###############################################################
#  Generated by:      Cadence Innovus 21.37-s075_1
#  OS:                Linux x86_64(Host ID caen-vnc-mi04.engin.umich.edu)
#  Generated on:      Fri Feb 14 15:29:48 2025
#  Design:            xor_sbox
###############################################################

VERSION 5.8 ;

BUSBITCHARS "[]" ;
DIVIDERCHAR "/" ;

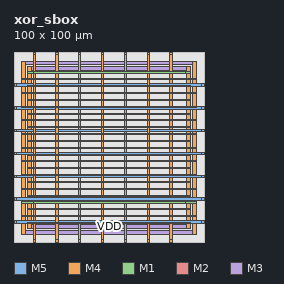
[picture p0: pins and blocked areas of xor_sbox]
MACRO xor_sbox
  CLASS BLOCK ;
  SIZE 100.000000 BY 100.000000 ;
  FOREIGN xor_sbox 0.000000 0.000000 ;
  ORIGIN 0 0 ;
  SYMMETRY X Y R90 ;
  PIN text[7]
    DIRECTION INPUT ;
    USE SIGNAL ;
  END text[7]
  PIN text[6]
    DIRECTION INPUT ;
    USE SIGNAL ;
  END text[6]
  PIN text[5]
    DIRECTION INPUT ;
    USE SIGNAL ;
  END text[5]
  PIN text[4]
    DIRECTION INPUT ;
    USE SIGNAL ;
  END text[4]
  PIN text[3]
    DIRECTION INPUT ;
    USE SIGNAL ;
  END text[3]
  PIN text[2]
    DIRECTION INPUT ;
    USE SIGNAL ;
  END text[2]
  PIN text[1]
    DIRECTION INPUT ;
    USE SIGNAL ;
  END text[1]
  PIN text[0]
    DIRECTION INPUT ;
    USE SIGNAL ;
  END text[0]
  PIN key[7]
    DIRECTION INPUT ;
    USE SIGNAL ;
  END key[7]
  PIN key[6]
    DIRECTION INPUT ;
    USE SIGNAL ;
  END key[6]
  PIN key[5]
    DIRECTION INPUT ;
    USE SIGNAL ;
  END key[5]
  PIN key[4]
    DIRECTION INPUT ;
    USE SIGNAL ;
  END key[4]
  PIN key[3]
    DIRECTION INPUT ;
    USE SIGNAL ;
  END key[3]
  PIN key[2]
    DIRECTION INPUT ;
    USE SIGNAL ;
  END key[2]
  PIN key[1]
    DIRECTION INPUT ;
    USE SIGNAL ;
  END key[1]
  PIN key[0]
    DIRECTION INPUT ;
    USE SIGNAL ;
  END key[0]
  PIN out0[7]
    DIRECTION OUTPUT ;
    USE SIGNAL ;
  END out0[7]
  PIN out0[6]
    DIRECTION OUTPUT ;
    USE SIGNAL ;
  END out0[6]
  PIN out0[5]
    DIRECTION OUTPUT ;
    USE SIGNAL ;
  END out0[5]
  PIN out0[4]
    DIRECTION OUTPUT ;
    USE SIGNAL ;
  END out0[4]
  PIN out0[3]
    DIRECTION OUTPUT ;
    USE SIGNAL ;
  END out0[3]
  PIN out0[2]
    DIRECTION OUTPUT ;
    USE SIGNAL ;
  END out0[2]
  PIN out0[1]
    DIRECTION OUTPUT ;
    USE SIGNAL ;
  END out0[1]
  PIN out0[0]
    DIRECTION OUTPUT ;
    USE SIGNAL ;
  END out0[0]
  PIN VDD
    DIRECTION INOUT ;
    USE POWER ;
    PORT
      LAYER M5 ;
        RECT 0.000000 10.000000 1.200000 11.200000 ;
    END
    PORT
      LAYER M5 ;
        RECT 98.800000 10.000000 100.000000 11.200000 ;
    END
    PORT
      LAYER M5 ;
        RECT 0.000000 34.000000 1.200000 35.200000 ;
    END
    PORT
      LAYER M5 ;
        RECT 98.800000 34.000000 100.000000 35.200000 ;
    END
    PORT
      LAYER M5 ;
        RECT 0.000000 58.000000 1.200000 59.200000 ;
    END
    PORT
      LAYER M5 ;
        RECT 98.800000 58.000000 100.000000 59.200000 ;
    END
    PORT
      LAYER M5 ;
        RECT 0.000000 82.000000 1.200000 83.200000 ;
    END
    PORT
      LAYER M5 ;
        RECT 98.800000 82.000000 100.000000 83.200000 ;
    END
    PORT
      LAYER M4 ;
        RECT 10.000000 0.000000 11.200000 1.200000 ;
    END
    PORT
      LAYER M4 ;
        RECT 10.000000 98.800000 11.200000 100.000000 ;
    END
    PORT
      LAYER M4 ;
        RECT 34.000000 0.000000 35.200000 1.200000 ;
    END
    PORT
      LAYER M4 ;
        RECT 34.000000 98.800000 35.200000 100.000000 ;
    END
    PORT
      LAYER M4 ;
        RECT 58.000000 0.000000 59.200000 1.200000 ;
    END
    PORT
      LAYER M4 ;
        RECT 58.000000 98.800000 59.200000 100.000000 ;
    END
    PORT
      LAYER M4 ;
        RECT 82.000000 0.000000 83.200000 1.200000 ;
    END
    PORT
      LAYER M4 ;
        RECT 82.000000 98.800000 83.200000 100.000000 ;
    END

# P/G power stripe data as pin
    PORT
      LAYER M1 ;
        RECT 7.000000 7.000000 93.000000 9.000000 ;
        RECT 10.000000 24.120000 90.000000 24.680000 ;
        RECT 10.000000 16.920000 90.000000 17.480000 ;
        RECT 10.000000 9.720000 90.000000 10.280000 ;
        RECT 10.000000 45.720000 90.000000 46.280000 ;
        RECT 10.000000 38.520000 90.000000 39.080000 ;
        RECT 10.000000 31.320000 90.000000 31.880000 ;
        RECT 7.000000 9.720000 10.000000 10.280000 ;
        RECT 7.000000 24.120000 10.000000 24.680000 ;
        RECT 7.000000 16.920000 10.000000 17.480000 ;
        RECT 7.000000 31.320000 10.000000 31.880000 ;
        RECT 7.000000 38.520000 10.000000 39.080000 ;
        RECT 7.000000 45.720000 10.000000 46.280000 ;
        RECT 90.000000 9.720000 93.000000 10.280000 ;
        RECT 90.000000 16.920000 93.000000 17.480000 ;
        RECT 90.000000 24.120000 93.000000 24.680000 ;
        RECT 90.000000 31.320000 93.000000 31.880000 ;
        RECT 90.000000 38.520000 93.000000 39.080000 ;
        RECT 90.000000 45.720000 93.000000 46.280000 ;
        RECT 10.000000 52.920000 90.000000 53.480000 ;
        RECT 10.000000 60.120000 90.000000 60.680000 ;
        RECT 10.000000 67.320000 90.000000 67.880000 ;
        RECT 10.000000 74.520000 90.000000 75.080000 ;
        RECT 10.000000 81.720000 90.000000 82.280000 ;
        RECT 10.000000 88.920000 90.000000 89.480000 ;
        RECT 7.000000 90.200000 93.000000 92.200000 ;
        RECT 7.000000 74.520000 10.000000 75.080000 ;
        RECT 7.000000 52.920000 10.000000 53.480000 ;
        RECT 7.000000 60.120000 10.000000 60.680000 ;
        RECT 7.000000 67.320000 10.000000 67.880000 ;
        RECT 7.000000 81.720000 10.000000 82.280000 ;
        RECT 7.000000 88.920000 10.000000 89.480000 ;
        RECT 90.000000 74.520000 93.000000 75.080000 ;
        RECT 90.000000 52.920000 93.000000 53.480000 ;
        RECT 90.000000 60.120000 93.000000 60.680000 ;
        RECT 90.000000 67.320000 93.000000 67.880000 ;
        RECT 90.000000 81.720000 93.000000 82.280000 ;
        RECT 90.000000 88.920000 93.000000 89.480000 ;
      LAYER M2 ;
        RECT 91.000000 7.000000 93.000000 92.200000 ;
        RECT 7.000000 7.000000 9.000000 92.200000 ;
      LAYER M3 ;
        RECT 7.000000 7.000000 93.000000 9.000000 ;
        RECT 7.000000 90.200000 93.000000 92.200000 ;
      LAYER M4 ;
        RECT 82.000000 0.000000 83.200000 100.000000 ;
        RECT 58.000000 0.000000 59.200000 100.000000 ;
        RECT 34.000000 0.000000 35.200000 100.000000 ;
        RECT 10.000000 0.000000 11.200000 100.000000 ;
        RECT 91.000000 7.000000 93.000000 92.200000 ;
        RECT 7.000000 7.000000 9.000000 92.200000 ;
      LAYER M5 ;
        RECT 0.000000 10.000000 100.000000 11.200000 ;
        RECT 0.000000 34.000000 100.000000 35.200000 ;
        RECT 0.000000 82.000000 100.000000 83.200000 ;
        RECT 0.000000 58.000000 100.000000 59.200000 ;
    END
# end of P/G power stripe data as pin

  END VDD
  PIN VSS
    DIRECTION INOUT ;
    USE GROUND ;
    PORT
      LAYER M5 ;
        RECT 0.000000 22.000000 1.200000 23.200000 ;
    END
    PORT
      LAYER M5 ;
        RECT 98.800000 22.000000 100.000000 23.200000 ;
    END
    PORT
      LAYER M5 ;
        RECT 0.000000 46.000000 1.200000 47.200000 ;
    END
    PORT
      LAYER M5 ;
        RECT 98.800000 46.000000 100.000000 47.200000 ;
    END
    PORT
      LAYER M5 ;
        RECT 0.000000 70.000000 1.200000 71.200000 ;
    END
    PORT
      LAYER M5 ;
        RECT 98.800000 70.000000 100.000000 71.200000 ;
    END
    PORT
      LAYER M4 ;
        RECT 22.000000 0.000000 23.200000 1.200000 ;
    END
    PORT
      LAYER M4 ;
        RECT 22.000000 98.800000 23.200000 100.000000 ;
    END
    PORT
      LAYER M4 ;
        RECT 46.000000 0.000000 47.200000 1.200000 ;
    END
    PORT
      LAYER M4 ;
        RECT 46.000000 98.800000 47.200000 100.000000 ;
    END
    PORT
      LAYER M4 ;
        RECT 70.000000 0.000000 71.200000 1.200000 ;
    END
    PORT
      LAYER M4 ;
        RECT 70.000000 98.800000 71.200000 100.000000 ;
    END

# P/G power stripe data as pin
    PORT
      LAYER M1 ;
        RECT 4.000000 4.000000 96.000000 6.000000 ;
        RECT 10.000000 20.520000 90.000000 21.080000 ;
        RECT 10.000000 13.320000 90.000000 13.880000 ;
        RECT 10.000000 49.320000 90.000000 49.880000 ;
        RECT 10.000000 42.120000 90.000000 42.680000 ;
        RECT 10.000000 34.920000 90.000000 35.480000 ;
        RECT 10.000000 27.720000 90.000000 28.280000 ;
        RECT 4.000000 13.320000 10.000000 13.880000 ;
        RECT 4.000000 20.520000 10.000000 21.080000 ;
        RECT 4.000000 27.720000 10.000000 28.280000 ;
        RECT 4.000000 34.920000 10.000000 35.480000 ;
        RECT 4.000000 42.120000 10.000000 42.680000 ;
        RECT 4.000000 49.320000 10.000000 49.880000 ;
        RECT 90.000000 13.320000 96.000000 13.880000 ;
        RECT 90.000000 20.520000 96.000000 21.080000 ;
        RECT 90.000000 27.720000 96.000000 28.280000 ;
        RECT 90.000000 34.920000 96.000000 35.480000 ;
        RECT 90.000000 42.120000 96.000000 42.680000 ;
        RECT 90.000000 49.320000 96.000000 49.880000 ;
        RECT 10.000000 56.520000 90.000000 57.080000 ;
        RECT 10.000000 63.720000 90.000000 64.280000 ;
        RECT 10.000000 70.920000 90.000000 71.480000 ;
        RECT 10.000000 78.120000 90.000000 78.680000 ;
        RECT 10.000000 85.320000 90.000000 85.880000 ;
        RECT 4.000000 93.200000 96.000000 95.200000 ;
        RECT 4.000000 56.520000 10.000000 57.080000 ;
        RECT 4.000000 63.720000 10.000000 64.280000 ;
        RECT 4.000000 70.920000 10.000000 71.480000 ;
        RECT 4.000000 78.120000 10.000000 78.680000 ;
        RECT 4.000000 85.320000 10.000000 85.880000 ;
        RECT 90.000000 56.520000 96.000000 57.080000 ;
        RECT 90.000000 63.720000 96.000000 64.280000 ;
        RECT 90.000000 70.920000 96.000000 71.480000 ;
        RECT 90.000000 78.120000 96.000000 78.680000 ;
        RECT 90.000000 85.320000 96.000000 85.880000 ;
      LAYER M2 ;
        RECT 94.000000 4.000000 96.000000 95.200000 ;
        RECT 4.000000 4.000000 6.000000 95.200000 ;
      LAYER M3 ;
        RECT 4.000000 4.000000 96.000000 6.000000 ;
        RECT 4.000000 93.200000 96.000000 95.200000 ;
      LAYER M4 ;
        RECT 70.000000 0.000000 71.200000 100.000000 ;
        RECT 46.000000 0.000000 47.200000 100.000000 ;
        RECT 22.000000 0.000000 23.200000 100.000000 ;
        RECT 94.000000 4.000000 96.000000 95.200000 ;
        RECT 4.000000 4.000000 6.000000 95.200000 ;
      LAYER M5 ;
        RECT 0.000000 22.000000 100.000000 23.200000 ;
        RECT 0.000000 46.000000 100.000000 47.200000 ;
        RECT 0.000000 70.000000 100.000000 71.200000 ;
    END
# end of P/G power stripe data as pin

  END VSS
  OBS
    LAYER M1 ;
      RECT 0.000000 97.120000 100.000000 100.000000 ;
      RECT 97.920000 91.280000 100.000000 97.120000 ;
      RECT 0.000000 91.280000 2.080000 97.120000 ;
      RECT 94.920000 87.800000 100.000000 91.280000 ;
      RECT 0.000000 87.800000 5.080000 91.280000 ;
      RECT 97.920000 83.400000 100.000000 87.800000 ;
      RECT 0.000000 83.400000 2.080000 87.800000 ;
      RECT 94.920000 80.600000 100.000000 83.400000 ;
      RECT 0.000000 80.600000 5.080000 83.400000 ;
      RECT 97.920000 76.200000 100.000000 80.600000 ;
      RECT 0.000000 76.200000 2.080000 80.600000 ;
      RECT 94.920000 73.400000 100.000000 76.200000 ;
      RECT 0.000000 73.400000 5.080000 76.200000 ;
      RECT 97.920000 69.000000 100.000000 73.400000 ;
      RECT 0.000000 69.000000 2.080000 73.400000 ;
      RECT 94.920000 66.200000 100.000000 69.000000 ;
      RECT 0.000000 66.200000 5.080000 69.000000 ;
      RECT 97.920000 61.800000 100.000000 66.200000 ;
      RECT 0.000000 61.800000 2.080000 66.200000 ;
      RECT 94.920000 59.000000 100.000000 61.800000 ;
      RECT 0.000000 59.000000 5.080000 61.800000 ;
      RECT 97.920000 54.600000 100.000000 59.000000 ;
      RECT 0.000000 54.600000 2.080000 59.000000 ;
      RECT 94.920000 51.800000 100.000000 54.600000 ;
      RECT 0.000000 51.800000 5.080000 54.600000 ;
      RECT 97.920000 47.400000 100.000000 51.800000 ;
      RECT 0.000000 47.400000 2.080000 51.800000 ;
      RECT 94.920000 44.600000 100.000000 47.400000 ;
      RECT 0.000000 44.600000 5.080000 47.400000 ;
      RECT 97.920000 40.200000 100.000000 44.600000 ;
      RECT 0.000000 40.200000 2.080000 44.600000 ;
      RECT 94.920000 37.400000 100.000000 40.200000 ;
      RECT 0.000000 37.400000 5.080000 40.200000 ;
      RECT 97.920000 33.000000 100.000000 37.400000 ;
      RECT 0.000000 33.000000 2.080000 37.400000 ;
      RECT 94.920000 30.200000 100.000000 33.000000 ;
      RECT 0.000000 30.200000 5.080000 33.000000 ;
      RECT 97.920000 25.800000 100.000000 30.200000 ;
      RECT 0.000000 25.800000 2.080000 30.200000 ;
      RECT 94.920000 23.000000 100.000000 25.800000 ;
      RECT 0.000000 23.000000 5.080000 25.800000 ;
      RECT 97.920000 18.600000 100.000000 23.000000 ;
      RECT 0.000000 18.600000 2.080000 23.000000 ;
      RECT 94.920000 15.800000 100.000000 18.600000 ;
      RECT 0.000000 15.800000 5.080000 18.600000 ;
      RECT 97.920000 11.400000 100.000000 15.800000 ;
      RECT 0.000000 11.400000 2.080000 15.800000 ;
      RECT 94.920000 7.920000 100.000000 11.400000 ;
      RECT 0.000000 7.920000 5.080000 11.400000 ;
      RECT 97.920000 2.080000 100.000000 7.920000 ;
      RECT 0.000000 2.080000 2.080000 7.920000 ;
      RECT 0.000000 0.000000 100.000000 2.080000 ;
    LAYER M2 ;
      RECT 0.000000 97.120000 100.000000 100.000000 ;
      RECT 7.920000 94.120000 92.080000 97.120000 ;
      RECT 10.920000 5.080000 89.080000 94.120000 ;
      RECT 97.920000 2.080000 100.000000 97.120000 ;
      RECT 7.920000 2.080000 92.080000 5.080000 ;
      RECT 0.000000 2.080000 2.080000 97.120000 ;
      RECT 0.000000 0.000000 100.000000 2.080000 ;
    LAYER M3 ;
      RECT 0.000000 97.120000 100.000000 100.000000 ;
      RECT 97.920000 91.280000 100.000000 97.120000 ;
      RECT 0.000000 91.280000 2.080000 97.120000 ;
      RECT 94.920000 88.280000 100.000000 91.280000 ;
      RECT 0.000000 88.280000 5.080000 91.280000 ;
      RECT 0.000000 10.920000 100.000000 88.280000 ;
      RECT 94.920000 7.920000 100.000000 10.920000 ;
      RECT 0.000000 7.920000 5.080000 10.920000 ;
      RECT 97.920000 2.080000 100.000000 7.920000 ;
      RECT 0.000000 2.080000 2.080000 7.920000 ;
      RECT 0.000000 0.000000 100.000000 2.080000 ;
    LAYER M4 ;
      RECT 85.120000 97.120000 100.000000 100.000000 ;
      RECT 0.000000 97.120000 8.080000 100.000000 ;
      RECT 85.120000 94.120000 92.080000 97.120000 ;
      RECT 7.920000 94.120000 8.080000 97.120000 ;
      RECT 85.120000 5.080000 89.080000 94.120000 ;
      RECT 97.920000 2.080000 100.000000 97.120000 ;
      RECT 85.120000 2.080000 92.080000 5.080000 ;
      RECT 7.920000 2.080000 8.080000 5.080000 ;
      RECT 0.000000 2.080000 2.080000 97.120000 ;
      RECT 85.120000 0.000000 100.000000 2.080000 ;
      RECT 73.120000 0.000000 80.080000 100.000000 ;
      RECT 61.120000 0.000000 68.080000 100.000000 ;
      RECT 49.120000 0.000000 56.080000 100.000000 ;
      RECT 37.120000 0.000000 44.080000 100.000000 ;
      RECT 25.120000 0.000000 32.080000 100.000000 ;
      RECT 13.120000 0.000000 20.080000 100.000000 ;
      RECT 0.000000 0.000000 8.080000 2.080000 ;
    LAYER M5 ;
      RECT 0.000000 85.120000 100.000000 100.000000 ;
      RECT 0.000000 73.120000 100.000000 80.080000 ;
      RECT 0.000000 61.120000 100.000000 68.080000 ;
      RECT 0.000000 49.120000 100.000000 56.080000 ;
      RECT 0.000000 37.120000 100.000000 44.080000 ;
      RECT 0.000000 25.120000 100.000000 32.080000 ;
      RECT 0.000000 13.120000 100.000000 20.080000 ;
      RECT 0.000000 0.000000 100.000000 8.080000 ;
    LAYER M6 ;
      RECT 0.000000 0.000000 100.000000 100.000000 ;
    LAYER MQ ;
      RECT 0.000000 0.000000 100.000000 100.000000 ;
    LAYER LM ;
      RECT 0.000000 0.000000 100.000000 100.000000 ;
  END
END xor_sbox

END LIBRARY
